// Mitsubishi GX Works2 project: 亮灯练习2   PLC: FX3U/FX3UC

PROGRAM MAIN
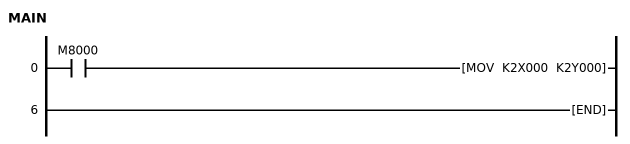
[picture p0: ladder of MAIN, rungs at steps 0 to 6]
0     LD      M8000
      MOV     K2X000 K2Y000
6     END
END_PROGRAM
